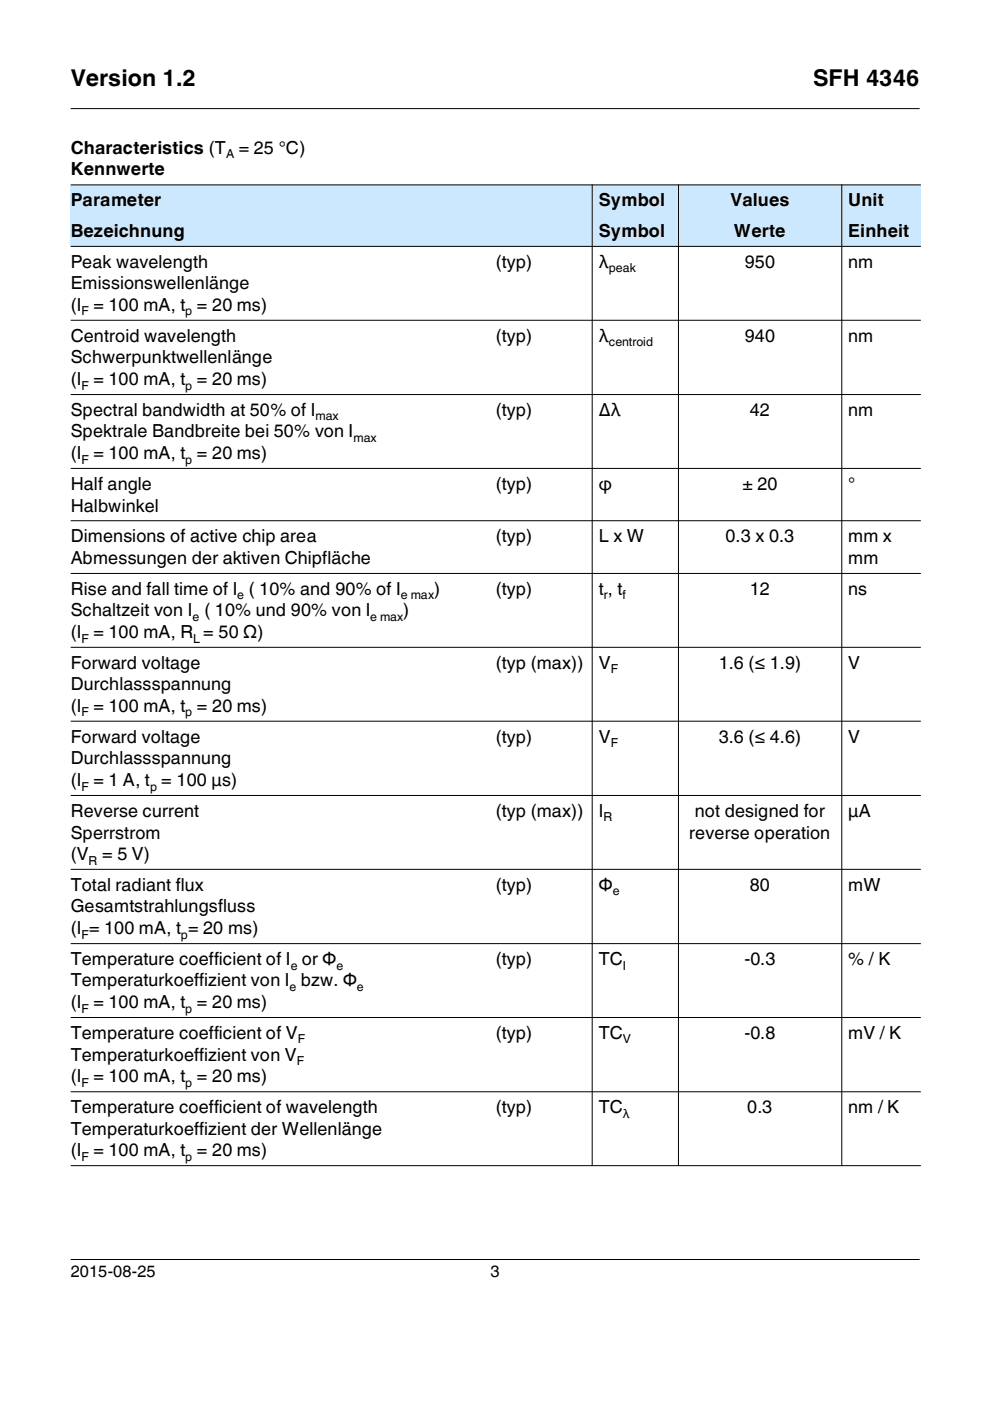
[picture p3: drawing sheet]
<svg xmlns="http://www.w3.org/2000/svg" width="210mm" height="297mm" viewBox="0 0 210 297" stroke-linecap="round" stroke-linejoin="round" font-family="sans-serif">
<defs><g id="words">
<g font-size="4.9">
<text x="15" y="18.3">Version 1.2</text>
<text x="172.4" y="18.3">SFH 4346</text>
</g>
<g font-size="3.8">
<text x="15" y="32.6">Characteristics (T</text>
<text x="50.6" y="32.6">= 25 °C)</text>
<text x="15" y="37.2">Kennwerte</text>
<text x="15" y="43.7">Parameter</text>
<text x="127" y="43.7">Symbol</text>
<text x="154.9" y="43.7">Values</text>
<text x="179.8" y="43.7">Unit</text>
<text x="15" y="50.2">Bezeichnung</text>
<text x="127" y="50.2">Symbol</text>
<text x="155.6" y="50.2">Werte</text>
<text x="179.8" y="50.2">Einheit</text>
<text x="15" y="56.7">Peak wavelength</text>
<text x="105.2" y="56.7">(typ)</text>
<text x="127" y="56.7">λ</text>
<text x="157.9" y="56.7">950</text>
<text x="179.8" y="56.7">nm</text>
<text x="15" y="61.3">Emissionswellenlänge</text>
<text x="15" y="66">(I = 100 mA, t = 20 ms)</text>
<text x="15" y="72.5">Centroid wavelength</text>
<text x="15" y="77">Schwerpunktwellenlänge</text>
<text x="105.2" y="72.5">(typ)</text>
<text x="127" y="72.5">λ</text>
<text x="157.9" y="72.5">940</text>
<text x="179.8" y="72.5">nm</text>
<text x="15" y="81.6">(I = 100 mA, t = 20 ms)</text>
<text x="15" y="88.1">Spectral bandwidth at 50% of I</text>
<text x="105.2" y="88.1">(typ)</text>
<text x="127" y="88.1">∆λ</text>
<text x="159" y="88.1">42</text>
<text x="179.8" y="88.1">nm</text>
<text x="15" y="92.7">Spektrale Bandbreite bei 50% von I</text>
<text x="15" y="97.4">(I = 100 mA, t = 20 ms)</text>
<text x="15" y="103.9">Half angle</text>
<text x="105.2" y="103.9">(typ)</text>
<text x="127" y="103.9">ϕ</text>
<text x="157.4" y="103.9">± 20</text>
<text x="179.8" y="103.9">°</text>
<text x="15" y="108.5">Halbwinkel</text>
<text x="15" y="115">Dimensions of active chip area</text>
<text x="15" y="119.5">Abmessungen der aktiven Chipfläche</text>
<text x="105.2" y="115">(typ)</text>
<text x="127" y="115">L x W</text>
<text x="153.8" y="115">0.3 x 0.3</text>
<text x="179.8" y="115">mm x</text>
<text x="179.8" y="119.5">mm</text>
<text x="15" y="126.1">Rise and fall time of I ( 10% and 90% of I</text>
<text x="15" y="130.6">Schaltzeit von I ( 10% und 90% von I</text>
<text x="85.5" y="130.6">)</text>
<text x="92" y="126.1">)</text>
<text x="105.2" y="126.1">(typ)</text>
<text x="127" y="126.1">t , t</text>
<text x="159" y="126.1">12</text>
<text x="179.8" y="126.1">ns</text>
<text x="15" y="135.2">(I = 100 mA, R = 50 Ω)</text>
<text x="15" y="141.8">Forward voltage</text>
<text x="105.2" y="141.8">(typ (max))</text>
<text x="127" y="141.8">V</text>
<text x="152.4" y="141.8">1.6 (≤ 1.9)</text>
<text x="179.8" y="141.8">V</text>
<text x="15" y="146.4">Durchlassspannung</text>
<text x="15" y="151">(I = 100 mA, t = 20 ms)</text>
<text x="15" y="157.5">Forward voltage</text>
<text x="105.2" y="157.5">(typ)</text>
<text x="127" y="157.5">V</text>
<text x="152.4" y="157.5">3.6 (≤ 4.6)</text>
<text x="179.8" y="157.5">V</text>
<text x="15" y="162.1">Durchlassspannung</text>
<text x="15" y="166.6">(I = 1 A, t = 100 µs)</text>
<text x="15" y="173.1">Reverse current</text>
<text x="105.2" y="173.1">(typ (max))</text>
<text x="127" y="173.1">I</text>
<text x="147.3" y="173.1">not designed for</text>
<text x="179.8" y="173.1">µA</text>
<text x="15" y="177.8">Sperrstrom</text>
<text x="146.1" y="177.8">reverse operation</text>
<text x="15" y="182.4">(V</text>
<text x="21.7" y="182.4">= 5 V)</text>
<text x="15" y="188.9">Total radiant flux</text>
<text x="105.2" y="188.9">(typ)</text>
<text x="127" y="188.9">Φ</text>
<text x="159" y="188.9">80</text>
<text x="179.8" y="188.9">mW</text>
<text x="15" y="193.5">Gesamtstrahlungsfluss</text>
<text x="15" y="198">(I = 100 mA, t = 20 ms)</text>
<text x="15" y="204.6">Temperature coefficient of I or Φ</text>
<text x="15" y="209.1">Temperaturkoeffizient von I bzw. Φ</text>
<text x="105.2" y="204.6">(typ)</text>
<text x="127" y="204.6">TC</text>
<text x="157.8" y="204.6">-0.3</text>
<text x="179.8" y="204.6">% / K</text>
<text x="15" y="213.8">(I = 100 mA, t = 20 ms)</text>
<text x="15" y="220.3">Temperature coefficient of V</text>
<text x="105.2" y="220.3">(typ)</text>
<text x="127" y="220.3">TC</text>
<text x="157.8" y="220.3">-0.8</text>
<text x="179.8" y="220.3">mV / K</text>
<text x="15" y="224.9">Temperaturkoeffizient von V</text>
<text x="15" y="229.4">(I = 100 mA, t = 20 ms)</text>
<text x="15" y="236">Temperature coefficient of wavelength</text>
<text x="105.2" y="236">(typ)</text>
<text x="127" y="236">TC</text>
<text x="158.4" y="236">0.3</text>
<text x="179.8" y="236">nm / K</text>
<text x="15" y="240.5">Temperaturkoeffizient der Wellenlänge</text>
<text x="15" y="245.1">(I = 100 mA, t = 20 ms)</text>
</g>
<g font-size="3.5">
<text x="15" y="270.8">2015-08-25</text>
<text x="104" y="270.8">3</text>
</g>
<g font-size="2.6">
<text x="47.9" y="33.5">A</text>
<text x="129.1" y="57.7">peak</text>
<text x="17.3" y="66.9">F</text>
<text x="39.3" y="66.9">p</text>
<text x="129.1" y="73.4">centroid</text>
<text x="17.3" y="82.6">F</text>
<text x="39.3" y="82.6">p</text>
<text x="66.9" y="89.2">max</text>
<text x="74.9" y="93.7">max</text>
<text x="17.3" y="98.3">F</text>
<text x="39.3" y="98.3">p</text>
<text x="40.8" y="131.7">e</text>
<text x="50.3" y="127.1">e</text>
<text x="78.5" y="131.7">e max</text>
<text x="85" y="127.1">e max</text>
<text x="128" y="127.1">r</text>
<text x="132" y="127.1">f</text>
<text x="17.3" y="136.2">F</text>
<text x="41" y="136.2">L</text>
<text x="129.5" y="142.7">F</text>
<text x="17.3" y="151.9">F</text>
<text x="39.3" y="151.9">p</text>
<text x="129.5" y="158.4">F</text>
<text x="17.3" y="167.6">F</text>
<text x="31.8" y="167.6">p</text>
<text x="127.9" y="174.2">R</text>
<text x="18.8" y="183.3">R</text>
<text x="130" y="189.8">e</text>
<text x="17.3" y="199.1">F</text>
<text x="38.4" y="199.1">p</text>
<text x="61.6" y="205.6">e</text>
<text x="71.4" y="205.6">e</text>
<text x="132.1" y="205.6">I</text>
<text x="17.3" y="214.7">F</text>
<text x="39.3" y="214.7">p</text>
<text x="61.4" y="210.1">e</text>
<text x="75.7" y="210.1">e</text>
<text x="63.2" y="221.2">F</text>
<text x="132.1" y="221.2">V</text>
<text x="62.9" y="225.8">F</text>
<text x="17.3" y="230.4">F</text>
<text x="39.3" y="230.4">p</text>
<text x="132.1" y="237">λ</text>
<text x="17.3" y="246.1">F</text>
<text x="39.3" y="246.1">p</text>
</g>
</g></defs>
<path d="M15 23h180M15 267h180" fill="none" stroke="#000" stroke-width=".21"/>
<g fill="#cce8ff">
<path d="M15 39.2h88.7v6.5h-88.7z"/>
<path d="M103.7 39.2h21.9v6.5h-21.9z"/>
<path d="M125.6 39.2h18.2v6.5h-18.2z"/>
<path d="M143.8 39.2h34.7v6.5h-34.7z"/>
<path d="M178.5 39.2h16.7v6.5h-16.7z"/>
<path d="M15 45.7h88.7v6.5h-88.7z"/>
<path d="M103.7 45.7h21.9v6.5h-21.9z"/>
<path d="M125.6 45.7h18.2v6.5h-18.2z"/>
<path d="M143.8 45.7h34.7v6.5h-34.7z"/>
<path d="M178.5 45.7h16.7v6.5h-16.7z"/>
</g>
<g fill="none" stroke="#000" stroke-width=".21">
<path d="M15 39.2h180.2M125.6 39.1v208.1M143.8 39.1v208.1M178.5 39.1v208.1M15 52.2h180.2M15 67.9h180.2M15 83.7h180.2M15 99.3h180.2M15 110.4h180.2M15 121.6h180.2M15 137.2h180.2M15 152.9h180.2"/>
<path d="M15 168.7h180.2M15 184.3h180.2M15 200.1h180.2M15 215.7h180.2M15 231.5h180.2M15 247.1h180.2"/>
</g>
<use href="#words"/>
</svg>
